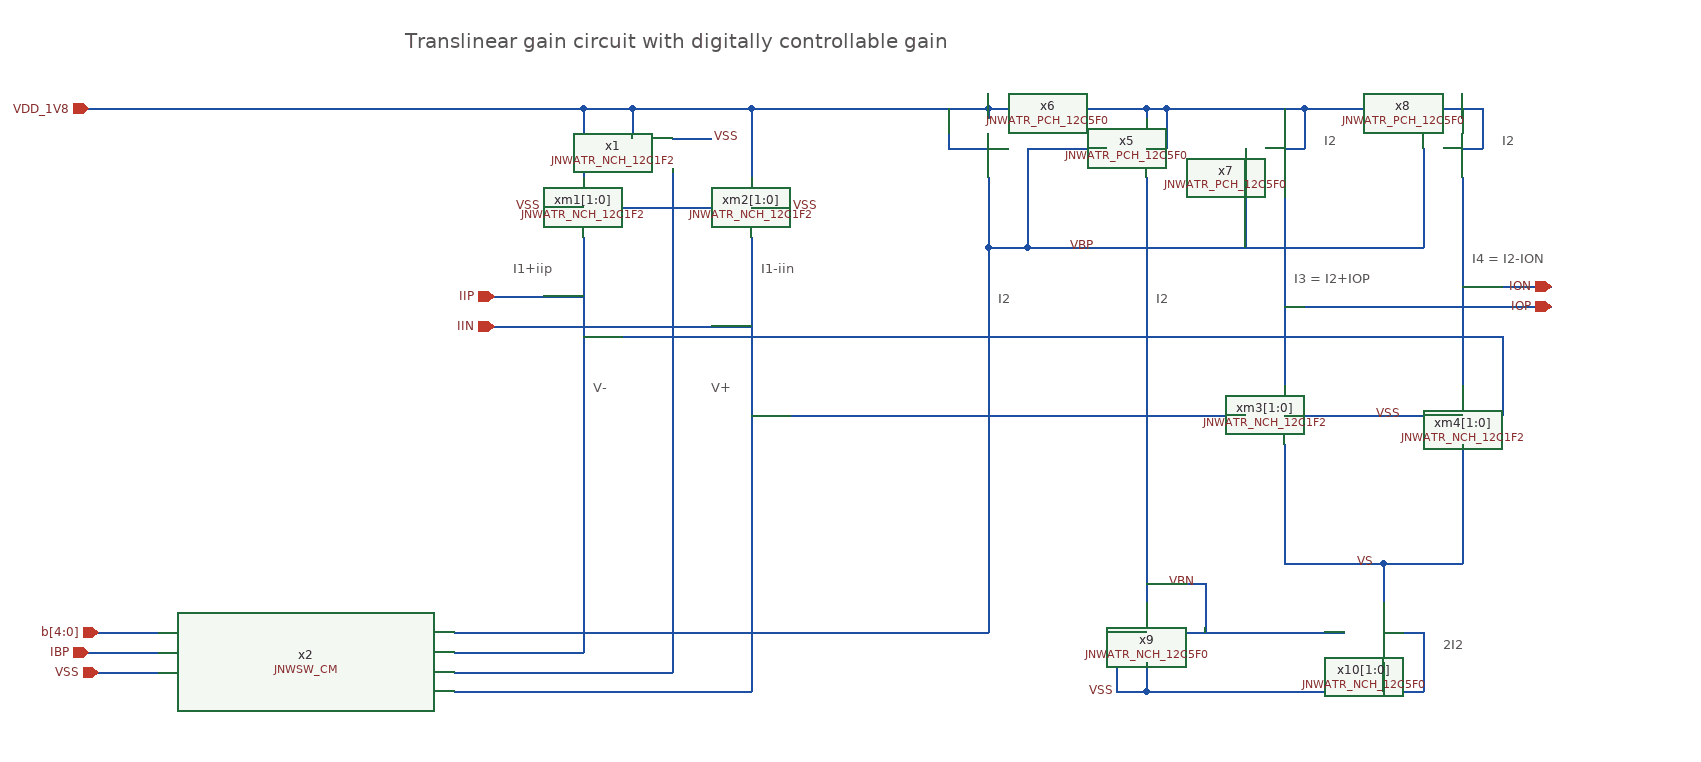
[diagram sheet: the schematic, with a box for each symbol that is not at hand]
v {xschem version=3.4.7 file_version=1.2}
G {}
K {}
V {}
S {}
E {}
T {Translinear gain circuit with digitally controllable gain} 430 -760 0 0 0.6 0.6 {}
T {I1+iip} 540 -530 0 0 0.4 0.4 {}
T {I1-iin} 790 -530 0 0 0.4 0.4 {}
T {2I2} 1480 -150 0 0 0.4 0.4 {}
T {V+} 740 -410 0 0 0.4 0.4 {}
T {V-} 620 -410 0 0 0.4 0.4 {}
T {I3 = I2+IOP} 1330 -520 0 0 0.4 0.4 {}
T {I4 = I2-ION} 1510 -540 0 0 0.4 0.4 {}
T {I2} 1540 -660 0 0 0.4 0.4 {}
T {I2} 1360 -660 0 0 0.4 0.4 {}
T {I2} 1030 -500 0 0 0.4 0.4 {}
T {I2} 1190 -500 0 0 0.4 0.4 {}
N 650 -580 740 -580 {
lab=#net1}
N 660 -680 660 -650 {
lab=VDD_1V8}
N 660 -680 700 -680 {
lab=VDD_1V8}
N 610 -680 610 -610 {
lab=VDD_1V8}
N 610 -680 660 -680 {
lab=VDD_1V8}
N 700 -680 780 -680 {
lab=VDD_1V8}
N 780 -680 780 -610 {
lab=VDD_1V8}
N 700 -650 740 -650 {
lab=VSS}
N 780 -580 820 -580 {
lab=VSS}
N 570 -580 610 -580 {
lab=VSS}
N 610 -550 610 -410 {
lab=IIP}
N 780 -550 780 -410 {
lab=IIN}
N 610 -410 610 -130 {
lab=IIP}
N 480 -130 610 -130 {
lab=IIP}
N 780 -410 780 -110 {
lab=IIN}
N 780 -110 780 -90 {
lab=IIN}
N 480 -90 780 -90 {
lab=IIN}
N 700 -120 700 -110 {
lab=#net1}
N 480 -110 700 -110 {
lab=#net1}
N 1020 -680 1020 -670 {
lab=VDD_1V8}
N 780 -680 1020 -680 {
lab=VDD_1V8}
N 1020 -610 1020 -540 {
lab=VBP}
N 1020 -540 1060 -540 {
lab=VBP}
N 1060 -640 1060 -540 {
lab=VBP}
N 980 -640 1020 -640 {
lab=VDD_1V8}
N 980 -680 980 -640 {
lab=VDD_1V8}
N 1060 -640 1140 -640 {
lab=VBP}
N 1020 -680 1180 -680 {
lab=VDD_1V8}
N 1180 -680 1180 -670 {
lab=VDD_1V8}
N 1180 -640 1200 -640 {
lab=VDD_1V8}
N 1200 -680 1200 -640 {
lab=VDD_1V8}
N 1180 -680 1200 -680 {
lab=VDD_1V8}
N 1320 -640 1340 -640 {
lab=VDD_1V8}
N 1340 -680 1340 -640 {
lab=VDD_1V8}
N 1500 -640 1520 -640 {
lab=VDD_1V8}
N 1520 -680 1520 -640 {
lab=VDD_1V8}
N 1220 -150 1380 -150 {
lab=VBN}
N 1150 -150 1180 -150 {
lab=VSS}
N 1150 -150 1150 -90 {
lab=VSS}
N 1150 -90 1180 -90 {
lab=VSS}
N 1180 -120 1180 -90 {
lab=VSS}
N 1180 -610 1180 -180 {
lab=VBN}
N 1320 -370 1500 -370 {
lab=VSS}
N 1320 -340 1320 -220 {
lab=VS}
N 1320 -220 1420 -220 {
lab=VS}
N 1420 -220 1420 -180 {
lab=VS}
N 1500 -340 1500 -220 {
lab=VS}
N 1420 -220 1500 -220 {
lab=VS}
N 1420 -150 1460 -150 {
lab=VSS}
N 1460 -150 1460 -90 {
lab=VSS}
N 1180 -90 1460 -90 {
lab=VSS}
N 1420 -120 1420 -90 {
lab=VSS}
N 1060 -540 1290 -540 {
lab=VBP}
N 1290 -540 1300 -540 {
lab=VBP}
N 1280 -640 1280 -540 {
lab=VBP}
N 1310 -540 1460 -540 {
lab=VBP}
N 1460 -640 1460 -540 {
lab=VBP}
N 1320 -610 1320 -400 {
lab=IOP}
N 1300 -540 1310 -540 {
lab=VBP}
N 1200 -680 1340 -680 {
lab=VDD_1V8}
N 1320 -680 1320 -670 {
lab=VDD_1V8}
N 1340 -680 1520 -680 {
lab=VDD_1V8}
N 1500 -680 1500 -670 {
lab=VDD_1V8}
N 1500 -610 1500 -400 {
lab=ION}
N 780 -370 1280 -370 {
lab=IIN}
N 1540 -450 1540 -370 {
lab=IIP}
N 610 -450 1540 -450 {
lab=IIP}
N 1240 -200 1240 -150 {
lab=VBN}
N 1180 -200 1240 -200 {
lab=VBN}
N 1500 -500 1590 -500 {
lab=ION}
N 1320 -480 1590 -480 {
lab=IOP}
N 520 -460 780 -460 {
lab=IIN}
N 520 -490 610 -490 {
lab=IIP}
N 480 -150 1020 -150 {
lab=VBP}
N 1020 -540 1020 -150 {
lab=VBP}
N 120 -150 180 -150 {
lab=b[4:0]}
N 110 -130 180 -130 {
lab=IBP}
N 120 -110 180 -110 {
lab=VSS}
N 110 -680 610 -680 {
lab=VDD_1V8}
N 700 -620 700 -580 {
lab=#net1}
N 700 -580 700 -120 {
lab=#net1}
C {devices/ipin.sym} 110 -680 0 0 {name=p1 lab=VDD_1V8}
C {devices/ipin.sym} 120 -110 0 0 {name=p2 lab=VSS}
C {devices/ipin.sym} 120 -150 0 0 {name=p3 lab=b[4:0]

}
C {devices/lab_wire.sym} 740 -650 0 1 {name=p6 sig_type=std_logic lab=VSS}
C {devices/lab_wire.sym} 820 -580 0 1 {name=p7 sig_type=std_logic lab=VSS}
C {devices/lab_wire.sym} 570 -580 0 0 {name=p8 sig_type=std_logic lab=VSS}
C {devices/opin.sym} 1590 -500 2 1 {name=p9 lab=ION

}
C {devices/opin.sym} 1590 -480 2 1 {name=p10 lab=IOP

}
C {devices/ipin.sym} 520 -490 0 0 {name=p11 lab=IIP

}
C {devices/ipin.sym} 520 -460 0 0 {name=p12 lab=IIN

}
C {devices/ipin.sym} 110 -130 0 0 {name=p13 lab=IBP

}
C {devices/lab_wire.sym} 1150 -90 0 0 {name=p14 sig_type=std_logic lab=VSS}
C {devices/lab_wire.sym} 1410 -370 0 1 {name=p4 sig_type=std_logic lab=VSS}
C {devices/lab_wire.sym} 1390 -220 0 1 {name=p5 sig_type=std_logic lab=VS}
C {devices/lab_wire.sym} 1100 -540 0 1 {name=p15 sig_type=std_logic lab=VBP}
C {devices/lab_wire.sym} 1200 -200 0 1 {name=p16 sig_type=std_logic lab=VBN}
C {/foss/designs/JNW_SV_SKY130A/design/JNW_SV_SKY130A/JNWSW_CM.sym} 330 -120 0 0 {name=x2}
C {/foss/designs/jnw_sv_sky130a/design/JNW_ATR_SKY130A/JNWATR_NCH_12C1F2.sym} 660 -650 0 0 {name=x1 }
C {/foss/designs/jnw_sv_sky130a/design/JNW_ATR_SKY130A/JNWATR_NCH_12C1F2.sym} 650 -580 0 1 {name=xm1[1:0]}
C {/foss/designs/jnw_sv_sky130a/design/JNW_ATR_SKY130A/JNWATR_NCH_12C1F2.sym} 740 -580 0 0 {name=xm2[1:0]}
C {/foss/designs/jnw_sv_sky130a/design/JNW_ATR_SKY130A/JNWATR_PCH_12C5F0.sym} 1060 -640 0 1 {name=x6 }
C {/foss/designs/jnw_sv_sky130a/design/JNW_ATR_SKY130A/JNWATR_PCH_12C5F0.sym} 1140 -640 0 0 {name=x5   }
C {/foss/designs/jnw_sv_sky130a/design/JNW_ATR_SKY130A/JNWATR_PCH_12C5F0.sym} 1280 -640 0 0 {name=x7   }
C {/foss/designs/jnw_sv_sky130a/design/JNW_ATR_SKY130A/JNWATR_PCH_12C5F0.sym} 1460 -640 0 0 {name=x8   }
C {/foss/designs/jnw_sv_sky130a/design/JNW_ATR_SKY130A/JNWATR_NCH_12C1F2.sym} 1280 -370 0 0 {name=xm3[1:0]

 }
C {/foss/designs/jnw_sv_sky130a/design/JNW_ATR_SKY130A/JNWATR_NCH_12C1F2.sym} 1540 -370 0 1 {name=xm4[1:0]

 }
C {/foss/designs/jnw_sv_sky130a/design/JNW_ATR_SKY130A/JNWATR_NCH_12C5F0.sym} 1380 -150 0 0 {name=x10[1:0]}
C {/foss/designs/jnw_sv_sky130a/design/JNW_ATR_SKY130A/JNWATR_NCH_12C5F0.sym} 1220 -150 0 1 {name=x9 }
C {title.sym} 160 -30 0 0 {name=l1 author="Carsten Wulf and Nithin Purushothama"}
